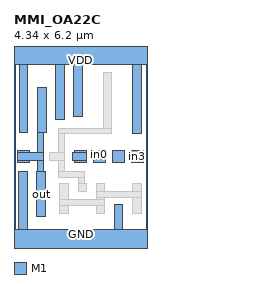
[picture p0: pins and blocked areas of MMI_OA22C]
MACRO MMI_OA22C
	CLASS CORE ;
	FOREIGN MMI_OA22C 0 0 ;
	SIZE 4.34 BY 6.2 ;
	SYMMETRY X Y ;
	SITE CORE1 ;
	PIN out
		DIRECTION output ;
		USE SIGNAL ;
		PORT
			LAYER M1 ;
			RECT 0.765 3.58 1.045 5.05 ;
			LAYER M1 ;
			RECT 0.12 2.93 0.5 2.98 ;
			LAYER M1 ;
			RECT 0.765 2.93 0.955 3.58 ;
			LAYER M1 ;
			RECT 0.12 2.655 0.955 2.93 ;
			LAYER M1 ;
			RECT 0.12 2.6 0.5 2.655 ;
			LAYER M1 ;
			RECT 0.765 2.295 0.955 2.655 ;
			LAYER M1 ;
			RECT 0.75 0.825 1.03 2.295 ;
		END
		AntennaDiffArea 1.2859 ;
	END out
	PIN in1
		DIRECTION input ;
		USE SIGNAL ;
		PORT
			LAYER M1 ;
			RECT 1.98 2.93 2.36 2.98 ;
			LAYER M1 ;
			RECT 1.895 2.65 2.36 2.93 ;
			LAYER M1 ;
			RECT 1.98 2.6 2.36 2.65 ;
		END
		AntennaGateArea 0.468 ;
	END in1
	PIN GND
		DIRECTION inout ;
		USE GROUND ;
		PORT
			LAYER M1 ;
			RECT 0.16 0.42 0.44 2.295 ;
			LAYER M1 ;
			RECT 3.27 0.42 3.55 1.225 ;
			LAYER M1 ;
			RECT 0 -0.42 4.34 0.42 ;
		END
	END GND
	PIN in2
		DIRECTION input ;
		USE SIGNAL ;
		PORT
			LAYER M1 ;
			RECT 3.22 2.6 3.6 2.98 ;
		END
		AntennaGateArea 0.468 ;
	END in2
	PIN VDD
		DIRECTION inout ;
		USE POWER ;
		PORT
			LAYER M1 ;
			RECT 0 5.78 4.34 6.62 ;
			LAYER M1 ;
			RECT 0.175 3.58 0.455 5.78 ;
			LAYER M1 ;
			RECT 1.355 3.99 1.635 5.78 ;
			LAYER M1 ;
			RECT 1.945 4.085 2.225 5.78 ;
			LAYER M1 ;
			RECT 3.875 3.525 4.155 5.78 ;
		END
	END VDD
	PIN in3
		DIRECTION input ;
		USE SIGNAL ;
		PORT
			LAYER M1 ;
			RECT 3.84 2.6 4.22 2.98 ;
		END
		AntennaGateArea 0.468 ;
	END in3
	PIN in0
		DIRECTION input ;
		USE SIGNAL ;
		PORT
			LAYER M1 ;
			RECT 2.565 2.7 2.98 2.98 ;
			LAYER M1 ;
			RECT 2.6 2.6 2.98 2.7 ;
		END
		AntennaGateArea 0.468 ;
	END in0
	OBS
		LAYER M1 ;
		RECT 2.915 3.715 3.195 5.535 ;
		LAYER M1 ;
		RECT 1.465 3.525 3.195 3.715 ;
		LAYER M1 ;
		RECT 1.465 2.935 1.66 3.525 ;
		LAYER M1 ;
		RECT 1.155 2.65 1.66 2.935 ;
		LAYER M1 ;
		RECT 1.465 2.31 1.66 2.65 ;
		LAYER M1 ;
		RECT 1.465 2.115 2.29 2.31 ;
		LAYER M1 ;
		RECT 2.095 1.915 2.29 2.115 ;
		LAYER M1 ;
		RECT 1.5 1.375 1.78 1.915 ;
		LAYER M1 ;
		RECT 2.09 1.635 2.37 1.915 ;
		LAYER M1 ;
		RECT 2.68 1.64 2.96 1.915 ;
		LAYER M1 ;
		RECT 3.875 1.64 4.155 1.915 ;
		LAYER M1 ;
		RECT 2.68 1.45 4.155 1.64 ;
		LAYER M1 ;
		RECT 2.68 1.375 2.96 1.45 ;
		LAYER M1 ;
		RECT 1.49 1.18 2.96 1.375 ;
		LAYER M1 ;
		RECT 1.5 0.945 1.78 1.18 ;
		LAYER M1 ;
		RECT 2.68 0.945 2.96 1.18 ;
		LAYER M1 ;
		RECT 3.875 0.945 4.155 1.45 ;
	END
END MMI_OA22C
